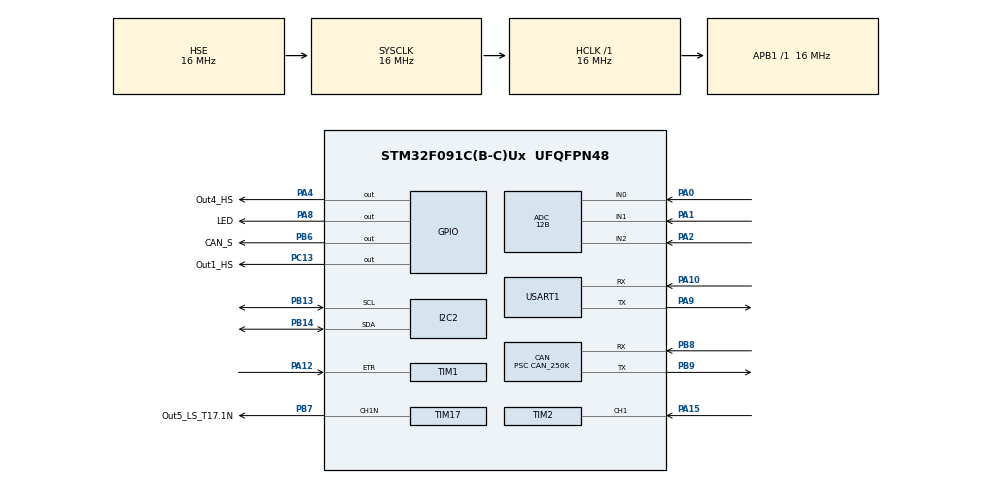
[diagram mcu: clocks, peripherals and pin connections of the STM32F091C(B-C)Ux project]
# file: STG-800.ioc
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ADC.ClockPrescaler=ADC_CLOCK_ASYNC_DIV1
ADC.ContinuousConvMode=DISABLE
ADC.DMAContinuousRequests=DISABLE
ADC.DataAlign=ADC_DATAALIGN_RIGHT
ADC.DiscontinuousConvMode=DISABLE
ADC.EOCSelection=ADC_EOC_SINGLE_CONV
ADC.EnableAnalogWatchDog=false
ADC.ExternalTrigConvEdge=ADC_EXTERNALTRIGCONVEDGE_NONE
ADC.LowPowerAutoPowerOff=DISABLE
ADC.LowPowerAutoWait=DISABLE
ADC.Overrun=ADC_OVR_DATA_PRESERVED
ADC.Resolution=ADC_RESOLUTION_12B
ADC.SamplingTime=ADC_SAMPLETIME_7CYCLES_5
ADC.ScanConvMode=ADC_SCAN_DIRECTION_FORWARD
CAN.ABOM=ENABLE
CAN.BS1=CAN_BS1_11TQ
CAN.BS2=CAN_BS2_4TQ
CAN.CalculateTimeBit=4000
CAN.CalculateTimeQuantum=250.0
CAN.Prescaler=CAN_250K
I2C2.Timing=0x00303D5B
Mcu.Family=STM32F0
Mcu.Name=STM32F091C(B-C)Ux
Mcu.Package=UFQFPN48
Mcu.UserConstants=CAN_1M,1;CAN_500K,2;CAN_250K,4;CAN_125K,8;CAN_100K,10;CAN_50K,20;ADC_IN1,1;ADC_IN2,2;ADC_IN3,3
NVIC.CEC_CAN_IRQn=true\:1\:0\:true\:true\:true\:1\:true
NVIC.RCC_CRS_IRQn=true\:0\:0\:false\:false\:true\:true
NVIC.TIM2_IRQn=true\:0\:0\:false\:false\:true\:true
NVIC.USART1_IRQn=true\:2\:0\:true\:true\:true\:3\:true
PA0.Mode=IN0
PA0.Signal=ADC_IN0
PA1.Mode=IN1
PA1.Signal=ADC_IN1
PA10.Mode=Asynchronous
PA10.Signal=USART1_RX
PA12.Signal=S_TIM1_ETR
PA13.Mode=Serial_Wire
PA13.Signal=SYS_SWDIO
PA14.Mode=Serial_Wire
PA14.Signal=SYS_SWCLK
PA15.Signal=S_TIM2_CH1_ETR
PA2.Mode=IN2
PA2.Signal=ADC_IN2
PA4.GPIO_Label=Out4_HS
PA4.Signal=GPIO_Output
PA8.GPIO_Label=LED
PA8.Signal=GPIO_Output
PA9.Mode=Asynchronous
PA9.Signal=USART1_TX
PB13.Mode=I2C
PB13.Signal=I2C2_SCL
PB14.Mode=I2C
PB14.Signal=I2C2_SDA
PB6.GPIO_Label=CAN_S
PB6.PinState=GPIO_PIN_SET
PB6.Signal=GPIO_Output
PB7.GPIO_Label=Out5_LS_T17.1N
PB7.Mode=PWM Generation1 CH1N
PB7.Signal=TIM17_CH1N
PB8.Mode=Master
PB8.Signal=CAN_RX
PB9.Mode=Master
PB9.Signal=CAN_TX
PC13.GPIO_Label=Out1_HS
PC13.Signal=GPIO_Output
PC14OSC32_IN.GPIO_Label=Out2_HS
PC14OSC32_IN.Signal=GPIO_Output
PC15OSC32_OUT.GPIO_Label=Out3_HS
PC15OSC32_OUT.Signal=GPIO_Output
PF0-OSC_IN.Mode=HSE-External-Oscillator
PF0-OSC_IN.Signal=RCC_OSC_IN
PF1-OSC_OUT.Mode=HSE-External-Oscillator
PF1-OSC_OUT.Signal=RCC_OSC_OUT
ProjectManager.HeapSize=0x200
ProjectManager.StackSize=0x400
ProjectManager.TargetToolchain=TrueSTUDIO
RCC.AHBFreq_Value=16000000
RCC.APB1Freq_Value=16000000
RCC.APB1TimFreq_Value=16000000
RCC.HCLKFreq_Value=16000000
RCC.HSE_VALUE=16000000
RCC.HSIState=RCC_HSI_ON
RCC.PLLMUL=RCC_PLL_MUL3
RCC.PLLSourceVirtual=RCC_PLLSOURCE_HSE
RCC.SYSCLKFreq_VALUE=16000000
RCC.SYSCLKSource=RCC_SYSCLKSOURCE_HSE
SH.S_TIM1_ETR.0=TIM1_ETR,TriggerSource_ETR
SH.S_TIM2_CH1_ETR.0=TIM2_CH1,Input_Capture1_from_TI1
SH.S_TIM2_CH1_ETR.1=TIM2_CH1,Input_Capture2_from_TI1
TIM17.Channel=TIM_CHANNEL_1
TIM17.Period=999
TIM17.Prescaler=15
TIM17.Pulse=500
TIM2.Channel-Input_Capture1_from_TI1=TIM_CHANNEL_1
TIM2.Channel-Input_Capture2_from_TI1=TIM_CHANNEL_2
TIM2.ICPolarity_CH2=TIM_INPUTCHANNELPOLARITY_FALLING
TIM2.Prescaler=3
USART1.VirtualMode-Asynchronous=VM_ASYNC
USART1.WordLength=UART_WORDLENGTH_8B
VP_ADC_TempSens_Input.Mode=IN-TempSens
VP_ADC_Vref_Input.Mode=IN-Vrefint
VP_IWDG_VS_IWDG.Mode=IWDG_Activate
VP_TIM17_VS_ClockSourceINT.Mode=Enable_Timer
VP_TIM1_VS_ControllerModeClock.Mode=Clock Mode
VP_TIM2_VS_ClockSourceINT.Mode=Internal
board=STG-800

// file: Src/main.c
/**
  ******************************************************************************
  * File Name          : main.c
  * Description        : Main program body
  ******************************************************************************
  *
  * COPYRIGHT(c) 2018 STMicroelectronics
  *
  * Redistribution and use in source and binary forms, with or without modification,
  * are permitted provided that the following conditions are met:
  *   1. Redistributions of source code must retain the above copyright notice,
  *      this list of conditions and the following disclaimer.
  *   2. Redistributions in binary form must reproduce the above copyright notice,
  *      this list of conditions and the following disclaimer in the documentation
  *      and/or other materials provided with the distribution.
  *   3. Neither the name of STMicroelectronics nor the names of its contributors
  *      may be used to endorse or promote products derived from this software
  *      without specific prior written permission.
  *
  * THIS SOFTWARE IS PROVIDED BY THE COPYRIGHT HOLDERS AND CONTRIBUTORS "AS IS"
  * AND ANY EXPRESS OR IMPLIED WARRANTIES, INCLUDING, BUT NOT LIMITED TO, THE
  * IMPLIED WARRANTIES OF MERCHANTABILITY AND FITNESS FOR A PARTICULAR PURPOSE ARE
  * DISCLAIMED. IN NO EVENT SHALL THE COPYRIGHT HOLDER OR CONTRIBUTORS BE LIABLE
  * FOR ANY DIRECT, INDIRECT, INCIDENTAL, SPECIAL, EXEMPLARY, OR CONSEQUENTIAL
  * DAMAGES (INCLUDING, BUT NOT LIMITED TO, PROCUREMENT OF SUBSTITUTE GOODS OR
  * SERVICES; LOSS OF USE, DATA, OR PROFITS; OR BUSINESS INTERRUPTION) HOWEVER
  * CAUSED AND ON ANY THEORY OF LIABILITY, WHETHER IN CONTRACT, STRICT LIABILITY,
  * OR TORT (INCLUDING NEGLIGENCE OR OTHERWISE) ARISING IN ANY WAY OUT OF THE USE
  * OF THIS SOFTWARE, EVEN IF ADVISED OF THE POSSIBILITY OF SUCH DAMAGE.
  *
  ******************************************************************************
  */
#include "main.h"
#include "stm32f0xx_hal.h"

ADC_HandleTypeDef hadc;

CAN_HandleTypeDef hcan;

I2C_HandleTypeDef hi2c2;

IWDG_HandleTypeDef hiwdg;

TIM_HandleTypeDef htim1;
TIM_HandleTypeDef htim2;
TIM_HandleTypeDef htim17;

UART_HandleTypeDef huart1;

/* USER CODE BEGIN PV */
/* Private variables ---------------------------------------------------------*/

/* USER CODE END PV */

void SystemClock_Config(void);
void Error_Handler(void);
static void MX_GPIO_Init(void);
static void MX_ADC_Init(void);
static void MX_CAN_Init(void);
static void MX_I2C2_Init(void);
static void MX_IWDG_Init(void);
static void MX_TIM1_Init(void);
static void MX_TIM2_Init(void);
static void MX_TIM17_Init(void);
static void MX_USART1_UART_Init(void);
static void MX_NVIC_Init(void);

void HAL_TIM_MspPostInit(TIM_HandleTypeDef *htim);

/* USER CODE BEGIN PFP */
/* Private function prototypes -----------------------------------------------*/

/* USER CODE END PFP */

int main(void)
{

  /* MCU Configuration----------------------------------------------------------*/

  /* Reset of all peripherals, Initializes the Flash interface and the Systick. */
  HAL_Init();

  /* Configure the system clock */
  SystemClock_Config();

  /* Initialize all configured peripherals */
  MX_GPIO_Init();
  MX_ADC_Init();
  MX_CAN_Init();
  MX_I2C2_Init();
  MX_IWDG_Init();
  MX_TIM1_Init();
  MX_TIM2_Init();
  MX_TIM17_Init();
  MX_USART1_UART_Init();

  /* Initialize interrupts */
  MX_NVIC_Init();

  /* Infinite loop */
  while (1)
  {

  }

}

/** System Clock Configuration
*/
void SystemClock_Config(void)
{

  RCC_OscInitTypeDef RCC_OscInitStruct;
  RCC_ClkInitTypeDef RCC_ClkInitStruct;
  RCC_PeriphCLKInitTypeDef PeriphClkInit;

    /**Initializes the CPU, AHB and APB busses clocks
    */
  RCC_OscInitStruct.OscillatorType = RCC_OSCILLATORTYPE_HSI14|RCC_OSCILLATORTYPE_LSI
                              |RCC_OSCILLATORTYPE_HSE;
  RCC_OscInitStruct.HSEState = RCC_HSE_ON;
  RCC_OscInitStruct.HSI14State = RCC_HSI14_ON;
  RCC_OscInitStruct.HSI14CalibrationValue = 16;
  RCC_OscInitStruct.LSIState = RCC_LSI_ON;
  RCC_OscInitStruct.PLL.PLLState = RCC_PLL_NONE;
  if (HAL_RCC_OscConfig(&RCC_OscInitStruct) != HAL_OK)
  {
    Error_Handler();
  }

    /**Initializes the CPU, AHB and APB busses clocks
    */
  RCC_ClkInitStruct.ClockType = RCC_CLOCKTYPE_HCLK|RCC_CLOCKTYPE_SYSCLK
                              |RCC_CLOCKTYPE_PCLK1;
  RCC_ClkInitStruct.SYSCLKSource = RCC_SYSCLKSOURCE_HSE;
  RCC_ClkInitStruct.AHBCLKDivider = RCC_SYSCLK_DIV1;
  RCC_ClkInitStruct.APB1CLKDivider = RCC_HCLK_DIV1;

  if (HAL_RCC_ClockConfig(&RCC_ClkInitStruct, FLASH_LATENCY_0) != HAL_OK)
  {
    Error_Handler();
  }

  PeriphClkInit.PeriphClockSelection = RCC_PERIPHCLK_USART1;
  PeriphClkInit.Usart1ClockSelection = RCC_USART1CLKSOURCE_PCLK1;
  if (HAL_RCCEx_PeriphCLKConfig(&PeriphClkInit) != HAL_OK)
  {
    Error_Handler();
  }

    /**Configure the Systick interrupt time
    */
  HAL_SYSTICK_Config(HAL_RCC_GetHCLKFreq()/1000);

    /**Configure the Systick
    */
  HAL_SYSTICK_CLKSourceConfig(SYSTICK_CLKSOURCE_HCLK);

  /* SysTick_IRQn interrupt configuration */
  HAL_NVIC_SetPriority(SysTick_IRQn, 0, 0);
}

/** NVIC Configuration
*/
static void MX_NVIC_Init(void)
{
  /* CEC_CAN_IRQn interrupt configuration */
  HAL_NVIC_SetPriority(CEC_CAN_IRQn, 1, 0);
  HAL_NVIC_EnableIRQ(CEC_CAN_IRQn);
  /* USART1_IRQn interrupt configuration */
  HAL_NVIC_SetPriority(USART1_IRQn, 2, 0);
  HAL_NVIC_EnableIRQ(USART1_IRQn);
}

/* ADC init function */
static void MX_ADC_Init(void)
{

  ADC_ChannelConfTypeDef sConfig;

    /**Configure the global features of the ADC (Clock, Resolution, Data Alignment and number of conversion)
    */
  hadc.Instance = ADC1;
  hadc.Init.ClockPrescaler = ADC_CLOCK_ASYNC_DIV1;
  hadc.Init.Resolution = ADC_RESOLUTION_12B;
  hadc.Init.DataAlign = ADC_DATAALIGN_RIGHT;
  hadc.Init.ScanConvMode = ADC_SCAN_DIRECTION_FORWARD;
  hadc.Init.EOCSelection = ADC_EOC_SINGLE_CONV;
  hadc.Init.LowPowerAutoWait = DISABLE;
  hadc.Init.LowPowerAutoPowerOff = DISABLE;
  hadc.Init.ContinuousConvMode = DISABLE;
  hadc.Init.DiscontinuousConvMode = DISABLE;
  hadc.Init.ExternalTrigConvEdge = ADC_EXTERNALTRIGCONVEDGE_NONE;
  hadc.Init.DMAContinuousRequests = DISABLE;
  hadc.Init.Overrun = ADC_OVR_DATA_PRESERVED;
  if (HAL_ADC_Init(&hadc) != HAL_OK)
  {
    Error_Handler();
  }

    /**Configure for the selected ADC regular channel to be converted.
    */
  sConfig.Channel = ADC_CHANNEL_0;
  sConfig.Rank = ADC_RANK_CHANNEL_NUMBER;
  sConfig.SamplingTime = ADC_SAMPLETIME_7CYCLES_5;
  if (HAL_ADC_ConfigChannel(&hadc, &sConfig) != HAL_OK)
  {
    Error_Handler();
  }

    /**Configure for the selected ADC regular channel to be converted.
    */
  sConfig.Channel = ADC_CHANNEL_1;
  if (HAL_ADC_ConfigChannel(&hadc, &sConfig) != HAL_OK)
  {
    Error_Handler();
  }

    /**Configure for the selected ADC regular channel to be converted.
    */
  sConfig.Channel = ADC_CHANNEL_2;
  if (HAL_ADC_ConfigChannel(&hadc, &sConfig) != HAL_OK)
  {
    Error_Handler();
  }

    /**Configure for the selected ADC regular channel to be converted.
    */
  sConfig.Channel = ADC_CHANNEL_TEMPSENSOR;
  if (HAL_ADC_ConfigChannel(&hadc, &sConfig) != HAL_OK)
  {
    Error_Handler();
  }

    /**Configure for the selected ADC regular channel to be converted.
    */
  sConfig.Channel = ADC_CHANNEL_VREFINT;
  if (HAL_ADC_ConfigChannel(&hadc, &sConfig) != HAL_OK)
  {
    Error_Handler();
  }

}

/* CAN init function */
static void MX_CAN_Init(void)
{

  hcan.Instance = CAN;
  hcan.Init.Prescaler = CAN_250K;
  hcan.Init.Mode = CAN_MODE_NORMAL;
  hcan.Init.SJW = CAN_SJW_1TQ;
  hcan.Init.BS1 = CAN_BS1_11TQ;
  hcan.Init.BS2 = CAN_BS2_4TQ;
  hcan.Init.TTCM = DISABLE;
  hcan.Init.ABOM = ENABLE;
  hcan.Init.AWUM = DISABLE;
  hcan.Init.NART = DISABLE;
  hcan.Init.RFLM = DISABLE;
  hcan.Init.TXFP = DISABLE;
  if (HAL_CAN_Init(&hcan) != HAL_OK)
  {
    Error_Handler();
  }

}

/* I2C2 init function */
static void MX_I2C2_Init(void)
{

  hi2c2.Instance = I2C2;
  hi2c2.Init.Timing = 0x00303D5B;
  hi2c2.Init.OwnAddress1 = 0;
  hi2c2.Init.AddressingMode = I2C_ADDRESSINGMODE_7BIT;
  hi2c2.Init.DualAddressMode = I2C_DUALADDRESS_DISABLE;
  hi2c2.Init.OwnAddress2 = 0;
  hi2c2.Init.OwnAddress2Masks = I2C_OA2_NOMASK;
  hi2c2.Init.GeneralCallMode = I2C_GENERALCALL_DISABLE;
  hi2c2.Init.NoStretchMode = I2C_NOSTRETCH_DISABLE;
  if (HAL_I2C_Init(&hi2c2) != HAL_OK)
  {
    Error_Handler();
  }

    /**Configure Analogue filter
    */
  if (HAL_I2CEx_ConfigAnalogFilter(&hi2c2, I2C_ANALOGFILTER_ENABLE) != HAL_OK)
  {
    Error_Handler();
  }

}

/* IWDG init function */
static void MX_IWDG_Init(void)
{

  hiwdg.Instance = IWDG;
  hiwdg.Init.Prescaler = IWDG_PRESCALER_4;
  hiwdg.Init.Window = 4095;
  hiwdg.Init.Reload = 4095;
  if (HAL_IWDG_Init(&hiwdg) != HAL_OK)
  {
    Error_Handler();
  }

}

/* TIM1 init function */
static void MX_TIM1_Init(void)
{

  TIM_SlaveConfigTypeDef sSlaveConfig;
  TIM_MasterConfigTypeDef sMasterConfig;

  htim1.Instance = TIM1;
  htim1.Init.Prescaler = 0;
  htim1.Init.CounterMode = TIM_COUNTERMODE_UP;
  htim1.Init.Period = 0;
  htim1.Init.ClockDivision = TIM_CLOCKDIVISION_DIV1;
  htim1.Init.RepetitionCounter = 0;
  if (HAL_TIM_Base_Init(&htim1) != HAL_OK)
  {
    Error_Handler();
  }

  sSlaveConfig.SlaveMode = TIM_SLAVEMODE_EXTERNAL1;
  sSlaveConfig.InputTrigger = TIM_TS_ETRF;
  sSlaveConfig.TriggerPolarity = TIM_TRIGGERPOLARITY_NONINVERTED;
  sSlaveConfig.TriggerPrescaler = TIM_TRIGGERPRESCALER_DIV1;
  sSlaveConfig.TriggerFilter = 0;
  if (HAL_TIM_SlaveConfigSynchronization(&htim1, &sSlaveConfig) != HAL_OK)
  {
    Error_Handler();
  }

  sMasterConfig.MasterOutputTrigger = TIM_TRGO_RESET;
  sMasterConfig.MasterSlaveMode = TIM_MASTERSLAVEMODE_DISABLE;
  if (HAL_TIMEx_MasterConfigSynchronization(&htim1, &sMasterConfig) != HAL_OK)
  {
    Error_Handler();
  }

}

/* TIM2 init function */
static void MX_TIM2_Init(void)
{

  TIM_ClockConfigTypeDef sClockSourceConfig;
  TIM_MasterConfigTypeDef sMasterConfig;
  TIM_IC_InitTypeDef sConfigIC;

  htim2.Instance = TIM2;
  htim2.Init.Prescaler = 3;
  htim2.Init.CounterMode = TIM_COUNTERMODE_UP;
  htim2.Init.Period = 0;
  htim2.Init.ClockDivision = TIM_CLOCKDIVISION_DIV1;
  if (HAL_TIM_Base_Init(&htim2) != HAL_OK)
  {
    Error_Handler();
  }

  sClockSourceConfig.ClockSource = TIM_CLOCKSOURCE_INTERNAL;
  if (HAL_TIM_ConfigClockSource(&htim2, &sClockSourceConfig) != HAL_OK)
  {
    Error_Handler();
  }

  if (HAL_TIM_IC_Init(&htim2) != HAL_OK)
  {
    Error_Handler();
  }

  sMasterConfig.MasterOutputTrigger = TIM_TRGO_RESET;
  sMasterConfig.MasterSlaveMode = TIM_MASTERSLAVEMODE_DISABLE;
  if (HAL_TIMEx_MasterConfigSynchronization(&htim2, &sMasterConfig) != HAL_OK)
  {
    Error_Handler();
  }

  sConfigIC.ICPolarity = TIM_INPUTCHANNELPOLARITY_RISING;
  sConfigIC.ICSelection = TIM_ICSELECTION_DIRECTTI;
  sConfigIC.ICPrescaler = TIM_ICPSC_DIV1;
  sConfigIC.ICFilter = 0;
  if (HAL_TIM_IC_ConfigChannel(&htim2, &sConfigIC, TIM_CHANNEL_1) != HAL_OK)
  {
    Error_Handler();
  }

  sConfigIC.ICPolarity = TIM_INPUTCHANNELPOLARITY_FALLING;
  sConfigIC.ICSelection = TIM_ICSELECTION_INDIRECTTI;
  if (HAL_TIM_IC_ConfigChannel(&htim2, &sConfigIC, TIM_CHANNEL_2) != HAL_OK)
  {
    Error_Handler();
  }

}

/* TIM17 init function */
static void MX_TIM17_Init(void)
{

  TIM_OC_InitTypeDef sConfigOC;
  TIM_BreakDeadTimeConfigTypeDef sBreakDeadTimeConfig;

  htim17.Instance = TIM17;
  htim17.Init.Prescaler = 15;
  htim17.Init.CounterMode = TIM_COUNTERMODE_UP;
  htim17.Init.Period = 999;
  htim17.Init.ClockDivision = TIM_CLOCKDIVISION_DIV1;
  htim17.Init.RepetitionCounter = 0;
  if (HAL_TIM_Base_Init(&htim17) != HAL_OK)
  {
    Error_Handler();
  }

  if (HAL_TIM_PWM_Init(&htim17) != HAL_OK)
  {
    Error_Handler();
  }

  sConfigOC.OCMode = TIM_OCMODE_PWM1;
  sConfigOC.Pulse = 500;
  sConfigOC.OCPolarity = TIM_OCPOLARITY_HIGH;
  sConfigOC.OCNPolarity = TIM_OCNPOLARITY_HIGH;
  sConfigOC.OCFastMode = TIM_OCFAST_DISABLE;
  sConfigOC.OCIdleState = TIM_OCIDLESTATE_RESET;
  sConfigOC.OCNIdleState = TIM_OCNIDLESTATE_RESET;
  if (HAL_TIM_PWM_ConfigChannel(&htim17, &sConfigOC, TIM_CHANNEL_1) != HAL_OK)
  {
    Error_Handler();
  }

  sBreakDeadTimeConfig.OffStateRunMode = TIM_OSSR_DISABLE;
  sBreakDeadTimeConfig.OffStateIDLEMode = TIM_OSSI_DISABLE;
  sBreakDeadTimeConfig.LockLevel = TIM_LOCKLEVEL_OFF;
  sBreakDeadTimeConfig.DeadTime = 0;
  sBreakDeadTimeConfig.BreakState = TIM_BREAK_DISABLE;
  sBreakDeadTimeConfig.BreakPolarity = TIM_BREAKPOLARITY_HIGH;
  sBreakDeadTimeConfig.AutomaticOutput = TIM_AUTOMATICOUTPUT_DISABLE;
  if (HAL_TIMEx_ConfigBreakDeadTime(&htim17, &sBreakDeadTimeConfig) != HAL_OK)
  {
    Error_Handler();
  }

  HAL_TIM_MspPostInit(&htim17);

}

/* USART1 init function */
static void MX_USART1_UART_Init(void)
{

  huart1.Instance = USART1;
  huart1.Init.BaudRate = 115200;
  huart1.Init.WordLength = UART_WORDLENGTH_8B;
  huart1.Init.StopBits = UART_STOPBITS_1;
  huart1.Init.Parity = UART_PARITY_NONE;
  huart1.Init.Mode = UART_MODE_TX_RX;
  huart1.Init.HwFlowCtl = UART_HWCONTROL_NONE;
  huart1.Init.OverSampling = UART_OVERSAMPLING_16;
  huart1.Init.OneBitSampling = UART_ONE_BIT_SAMPLE_DISABLE;
  huart1.AdvancedInit.AdvFeatureInit = UART_ADVFEATURE_NO_INIT;
  if (HAL_UART_Init(&huart1) != HAL_OK)
  {
    Error_Handler();
  }

}

/** Configure pins as
        * Analog
        * Input
        * Output
        * EVENT_OUT
        * EXTI
        * Free pins are configured automatically as Analog (this feature is enabled through
        * the Code Generation settings)
*/
static void MX_GPIO_Init(void)
{

  GPIO_InitTypeDef GPIO_InitStruct;

  /* GPIO Ports Clock Enable */
  __HAL_RCC_GPIOC_CLK_ENABLE();
  __HAL_RCC_GPIOF_CLK_ENABLE();
  __HAL_RCC_GPIOA_CLK_ENABLE();
  __HAL_RCC_GPIOB_CLK_ENABLE();

  /*Configure GPIO pin Output Level */
  HAL_GPIO_WritePin(GPIOC, Out1_HS_Pin|Out2_HS_Pin|Out3_HS_Pin, GPIO_PIN_RESET);

  /*Configure GPIO pin Output Level */
  HAL_GPIO_WritePin(GPIOA, Out4_HS_Pin|LED_Pin, GPIO_PIN_RESET);

  /*Configure GPIO pin Output Level */
  HAL_GPIO_WritePin(CAN_S_GPIO_Port, CAN_S_Pin, GPIO_PIN_SET);

  /*Configure GPIO pins : Out1_HS_Pin Out2_HS_Pin Out3_HS_Pin */
  GPIO_InitStruct.Pin = Out1_HS_Pin|Out2_HS_Pin|Out3_HS_Pin;
  GPIO_InitStruct.Mode = GPIO_MODE_OUTPUT_PP;
  GPIO_InitStruct.Pull = GPIO_NOPULL;
  GPIO_InitStruct.Speed = GPIO_SPEED_FREQ_LOW;
  HAL_GPIO_Init(GPIOC, &GPIO_InitStruct);

  /*Configure GPIO pins : PA3 PA5 PA6 PA7
                           PA11 */
  GPIO_InitStruct.Pin = GPIO_PIN_3|GPIO_PIN_5|GPIO_PIN_6|GPIO_PIN_7
                          |GPIO_PIN_11;
  GPIO_InitStruct.Mode = GPIO_MODE_ANALOG;
  GPIO_InitStruct.Pull = GPIO_NOPULL;
  HAL_GPIO_Init(GPIOA, &GPIO_InitStruct);

  /*Configure GPIO pins : Out4_HS_Pin LED_Pin */
  GPIO_InitStruct.Pin = Out4_HS_Pin|LED_Pin;
  GPIO_InitStruct.Mode = GPIO_MODE_OUTPUT_PP;
  GPIO_InitStruct.Pull = GPIO_NOPULL;
  GPIO_InitStruct.Speed = GPIO_SPEED_FREQ_LOW;
  HAL_GPIO_Init(GPIOA, &GPIO_InitStruct);

  /*Configure GPIO pins : PB0 PB1 PB2 PB10
                           PB11 PB12 PB15 PB3
                           PB4 PB5 */
  GPIO_InitStruct.Pin = GPIO_PIN_0|GPIO_PIN_1|GPIO_PIN_2|GPIO_PIN_10
                          |GPIO_PIN_11|GPIO_PIN_12|GPIO_PIN_15|GPIO_PIN_3
                          |GPIO_PIN_4|GPIO_PIN_5;
  GPIO_InitStruct.Mode = GPIO_MODE_ANALOG;
  GPIO_InitStruct.Pull = GPIO_NOPULL;
  HAL_GPIO_Init(GPIOB, &GPIO_InitStruct);

  /*Configure GPIO pin : CAN_S_Pin */
  GPIO_InitStruct.Pin = CAN_S_Pin;
  GPIO_InitStruct.Mode = GPIO_MODE_OUTPUT_PP;
  GPIO_InitStruct.Pull = GPIO_NOPULL;
  GPIO_InitStruct.Speed = GPIO_SPEED_FREQ_LOW;
  HAL_GPIO_Init(CAN_S_GPIO_Port, &GPIO_InitStruct);

  /*Configure GPIO pin : PF11 */
  GPIO_InitStruct.Pin = GPIO_PIN_11;
  GPIO_InitStruct.Mode = GPIO_MODE_ANALOG;
  GPIO_InitStruct.Pull = GPIO_NOPULL;
  HAL_GPIO_Init(GPIOF, &GPIO_InitStruct);

}

void Error_Handler(void)
{
  while(1)
  {
  }
}

/************************ (C) COPYRIGHT STMicroelectronics *****END OF FILE****/
